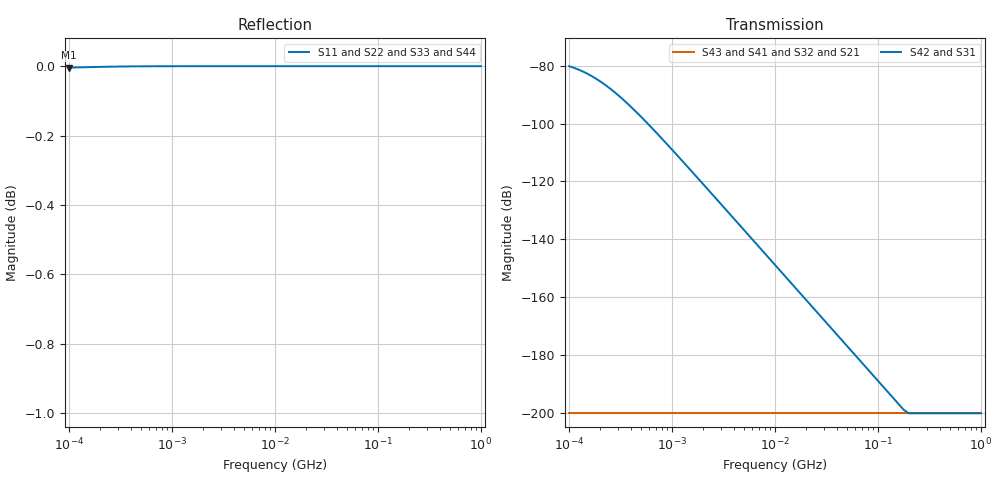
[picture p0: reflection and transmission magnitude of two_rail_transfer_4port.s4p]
# Hz S RI R 50
! golden: two_rail_transfer_4port
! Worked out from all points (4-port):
!   81 points, 100 kHz to 1 GHz, reference 50 ohm
!   strongest paths, dB at 100 kHz, 1 MHz, 10 MHz, 100 MHz, 1 GHz:
!     S42: -80.2, -109.0, -148.8, -188.8, -
!     S31: -80.2, -109.0, -148.8, -188.8, -
!     S43: -, -, -, -, -
!     S41: -, -, -, -, -
!     S32: -, -, -, -, -
!     S21: -, -, -, -, -
!   lowest |S11| = 0.0 dB at 100 kHz (marker M1)
!   |S11| at or under -10 dB: nowhere
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100000  -0.9995 -0.00034  0 0  4.36e-05 -8.73e-05  0 0
        0 0  -0.9995 -0.00034  0 0  4.36e-05 -8.73e-05
        4.36e-05 -8.73e-05  0 0  -0.9991 -0.000484  0 0
        0 0  4.36e-05 -8.73e-05  0 0  -0.9991 -0.000484
223872.1  -0.9998 -0.000321  0 0  -1.39e-05 -4.44e-05  0 0
          0 0  -0.9998 -0.000321  0 0  -1.39e-05 -4.44e-05
          -1.39e-05 -4.44e-05  0 0  -0.9995 -0.000562  0 0
          0 0  -1.39e-05 -4.44e-05  0 0  -0.9995 -0.000562
446683.6  -0.9999 -0.000205  0 0  -1.21e-05 -1.04e-05  0 0
          0 0  -0.9999 -0.000205  0 0  -1.21e-05 -1.04e-05
          -1.21e-05 -1.04e-05  0 0  -0.9998 -0.000408  0 0
          0 0  -1.21e-05 -1.04e-05  0 0  -0.9998 -0.000408
891250.9  -1 -0.000111  0 0  -4.12e-06 -1.6e-06  0 0
          0 0  -1 -0.000111  0 0  -4.12e-06 -1.6e-06
          -4.12e-06 -1.6e-06  0 0  -1 -0.000231  0 0
          0 0  -4.12e-06 -1.6e-06  0 0  -1 -0.000231
1995262  -1 -5.05e-05  0 0  -8.95e-07 -1.51e-07  0 0
         0 0  -1 -5.05e-05  0 0  -8.95e-07 -1.51e-07
         -8.95e-07 -1.51e-07  0 0  -1 -0.000107  0 0
         0 0  -8.95e-07 -1.51e-07  0 0  -1 -0.000107
6309573  -1 -1.6e-05  0 0  -9.12e-08 -4.83e-09  0 0
         0 0  -1 -1.6e-05  0 0  -9.12e-08 -4.83e-09
         -9.12e-08 -4.83e-09  0 0  -1 -3.41e-05  0 0
         0 0  -9.12e-08 -4.83e-09  0 0  -1 -3.41e-05
1e9  -1 -1.01e-07  0 0  -3.64e-12 -1.21e-15  0 0
     0 0  -1 -1.01e-07  0 0  -3.64e-12 -1.21e-15
     -3.64e-12 -1.21e-15  0 0  -1 -2.16e-07  0 0
     0 0  -3.64e-12 -1.21e-15  0 0  -1 -2.16e-07
